VERSION 5.8 ;
BUSBITCHARS "[]" ;
DIVIDERCHAR "/" ;
UNITS
    DATABASE MICRONS 1000 ;
END UNITS

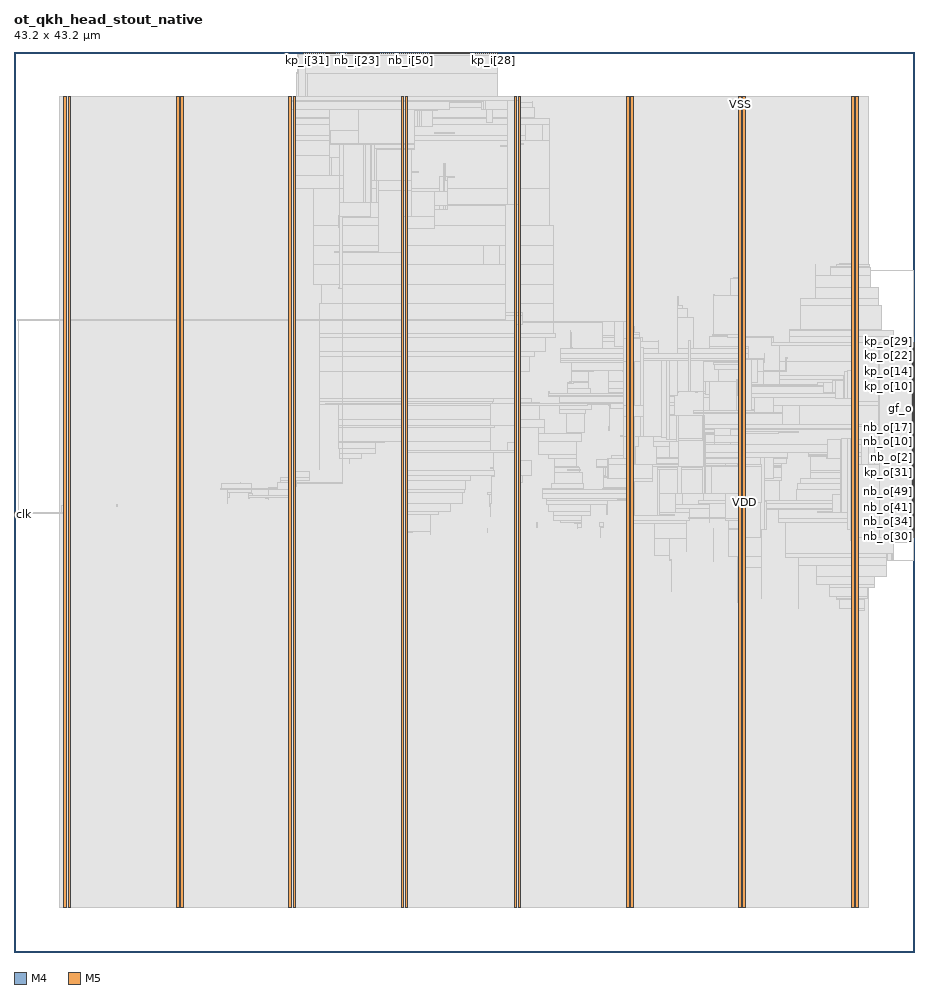
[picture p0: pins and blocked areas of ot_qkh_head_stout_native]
MACRO ot_qkh_head_stout_native
  FOREIGN ot_qkh_head_stout_native 0 0 ;
  CLASS BLOCK ;
  SIZE 43.2 BY 43.2 ;
  PIN clk
    DIRECTION INPUT ;
    USE SIGNAL ;
    PORT
      LAYER M4 ;
        RECT  0 20.976 0.084 21 ;
    END
  END clk
  PIN gf_i
    DIRECTION INPUT ;
    USE SIGNAL ;
    PORT
      LAYER M5 ;
        RECT  20.208 43.116 20.232 43.2 ;
    END
  END gf_i
  PIN gf_o
    DIRECTION OUTPUT ;
    USE SIGNAL ;
    PORT
      LAYER M4 ;
        RECT  43.116 26.064 43.2 26.088 ;
    END
  END gf_o
  PIN kp_i[0]
    DIRECTION INPUT ;
    USE SIGNAL ;
    PORT
      LAYER M5 ;
        RECT  20.304 43.116 20.328 43.2 ;
    END
  END kp_i[0]
  PIN kp_i[10]
    DIRECTION INPUT ;
    USE SIGNAL ;
    PORT
      LAYER M5 ;
        RECT  21.264 43.116 21.288 43.2 ;
    END
  END kp_i[10]
  PIN kp_i[11]
    DIRECTION INPUT ;
    USE SIGNAL ;
    PORT
      LAYER M5 ;
        RECT  21.36 43.116 21.384 43.2 ;
    END
  END kp_i[11]
  PIN kp_i[12]
    DIRECTION INPUT ;
    USE SIGNAL ;
    PORT
      LAYER M5 ;
        RECT  21.456 43.116 21.48 43.2 ;
    END
  END kp_i[12]
  PIN kp_i[13]
    DIRECTION INPUT ;
    USE SIGNAL ;
    PORT
      LAYER M5 ;
        RECT  21.552 43.116 21.576 43.2 ;
    END
  END kp_i[13]
  PIN kp_i[14]
    DIRECTION INPUT ;
    USE SIGNAL ;
    PORT
      LAYER M5 ;
        RECT  21.648 43.116 21.672 43.2 ;
    END
  END kp_i[14]
  PIN kp_i[15]
    DIRECTION INPUT ;
    USE SIGNAL ;
    PORT
      LAYER M5 ;
        RECT  21.744 43.116 21.768 43.2 ;
    END
  END kp_i[15]
  PIN kp_i[16]
    DIRECTION INPUT ;
    USE SIGNAL ;
    PORT
      LAYER M5 ;
        RECT  21.84 43.116 21.864 43.2 ;
    END
  END kp_i[16]
  PIN kp_i[17]
    DIRECTION INPUT ;
    USE SIGNAL ;
    PORT
      LAYER M5 ;
        RECT  21.936 43.116 21.96 43.2 ;
    END
  END kp_i[17]
  PIN kp_i[18]
    DIRECTION INPUT ;
    USE SIGNAL ;
    PORT
      LAYER M5 ;
        RECT  22.032 43.116 22.056 43.2 ;
    END
  END kp_i[18]
  PIN kp_i[19]
    DIRECTION INPUT ;
    USE SIGNAL ;
    PORT
      LAYER M5 ;
        RECT  22.128 43.116 22.152 43.2 ;
    END
  END kp_i[19]
  PIN kp_i[1]
    DIRECTION INPUT ;
    USE SIGNAL ;
    PORT
      LAYER M5 ;
        RECT  20.4 43.116 20.424 43.2 ;
    END
  END kp_i[1]
  PIN kp_i[20]
    DIRECTION INPUT ;
    USE SIGNAL ;
    PORT
      LAYER M5 ;
        RECT  22.224 43.116 22.248 43.2 ;
    END
  END kp_i[20]
  PIN kp_i[21]
    DIRECTION INPUT ;
    USE SIGNAL ;
    PORT
      LAYER M5 ;
        RECT  22.32 43.116 22.344 43.2 ;
    END
  END kp_i[21]
  PIN kp_i[22]
    DIRECTION INPUT ;
    USE SIGNAL ;
    PORT
      LAYER M5 ;
        RECT  22.416 43.116 22.44 43.2 ;
    END
  END kp_i[22]
  PIN kp_i[23]
    DIRECTION INPUT ;
    USE SIGNAL ;
    PORT
      LAYER M5 ;
        RECT  22.512 43.116 22.536 43.2 ;
    END
  END kp_i[23]
  PIN kp_i[24]
    DIRECTION INPUT ;
    USE SIGNAL ;
    PORT
      LAYER M5 ;
        RECT  22.608 43.116 22.632 43.2 ;
    END
  END kp_i[24]
  PIN kp_i[25]
    DIRECTION INPUT ;
    USE SIGNAL ;
    PORT
      LAYER M5 ;
        RECT  22.704 43.116 22.728 43.2 ;
    END
  END kp_i[25]
  PIN kp_i[26]
    DIRECTION INPUT ;
    USE SIGNAL ;
    PORT
      LAYER M5 ;
        RECT  22.8 43.116 22.824 43.2 ;
    END
  END kp_i[26]
  PIN kp_i[27]
    DIRECTION INPUT ;
    USE SIGNAL ;
    PORT
      LAYER M5 ;
        RECT  22.896 43.116 22.92 43.2 ;
    END
  END kp_i[27]
  PIN kp_i[28]
    DIRECTION INPUT ;
    USE SIGNAL ;
    PORT
      LAYER M5 ;
        RECT  22.992 43.116 23.016 43.2 ;
    END
  END kp_i[28]
  PIN kp_i[29]
    DIRECTION INPUT ;
    USE SIGNAL ;
    PORT
      LAYER M5 ;
        RECT  23.088 43.116 23.112 43.2 ;
    END
  END kp_i[29]
  PIN kp_i[2]
    DIRECTION INPUT ;
    USE SIGNAL ;
    PORT
      LAYER M5 ;
        RECT  20.496 43.116 20.52 43.2 ;
    END
  END kp_i[2]
  PIN kp_i[30]
    DIRECTION INPUT ;
    USE SIGNAL ;
    PORT
      LAYER M5 ;
        RECT  23.184 43.116 23.208 43.2 ;
    END
  END kp_i[30]
  PIN kp_i[31]
    DIRECTION INPUT ;
    USE SIGNAL ;
    PORT
      LAYER M5 ;
        RECT  14.064 43.116 14.088 43.2 ;
    END
  END kp_i[31]
  PIN kp_i[3]
    DIRECTION INPUT ;
    USE SIGNAL ;
    PORT
      LAYER M5 ;
        RECT  20.592 43.116 20.616 43.2 ;
    END
  END kp_i[3]
  PIN kp_i[4]
    DIRECTION INPUT ;
    USE SIGNAL ;
    PORT
      LAYER M5 ;
        RECT  20.688 43.116 20.712 43.2 ;
    END
  END kp_i[4]
  PIN kp_i[5]
    DIRECTION INPUT ;
    USE SIGNAL ;
    PORT
      LAYER M5 ;
        RECT  20.784 43.116 20.808 43.2 ;
    END
  END kp_i[5]
  PIN kp_i[6]
    DIRECTION INPUT ;
    USE SIGNAL ;
    PORT
      LAYER M5 ;
        RECT  20.88 43.116 20.904 43.2 ;
    END
  END kp_i[6]
  PIN kp_i[7]
    DIRECTION INPUT ;
    USE SIGNAL ;
    PORT
      LAYER M5 ;
        RECT  20.976 43.116 21 43.2 ;
    END
  END kp_i[7]
  PIN kp_i[8]
    DIRECTION INPUT ;
    USE SIGNAL ;
    PORT
      LAYER M5 ;
        RECT  21.072 43.116 21.096 43.2 ;
    END
  END kp_i[8]
  PIN kp_i[9]
    DIRECTION INPUT ;
    USE SIGNAL ;
    PORT
      LAYER M5 ;
        RECT  21.168 43.116 21.192 43.2 ;
    END
  END kp_i[9]
  PIN kp_o[0]
    DIRECTION OUTPUT ;
    USE SIGNAL ;
    PORT
      LAYER M4 ;
        RECT  43.116 26.16 43.2 26.184 ;
    END
  END kp_o[0]
  PIN kp_o[10]
    DIRECTION OUTPUT ;
    USE SIGNAL ;
    PORT
      LAYER M4 ;
        RECT  43.116 27.12 43.2 27.144 ;
    END
  END kp_o[10]
  PIN kp_o[11]
    DIRECTION OUTPUT ;
    USE SIGNAL ;
    PORT
      LAYER M4 ;
        RECT  43.116 27.216 43.2 27.24 ;
    END
  END kp_o[11]
  PIN kp_o[12]
    DIRECTION OUTPUT ;
    USE SIGNAL ;
    PORT
      LAYER M4 ;
        RECT  43.116 27.312 43.2 27.336 ;
    END
  END kp_o[12]
  PIN kp_o[13]
    DIRECTION OUTPUT ;
    USE SIGNAL ;
    PORT
      LAYER M4 ;
        RECT  43.116 27.408 43.2 27.432 ;
    END
  END kp_o[13]
  PIN kp_o[14]
    DIRECTION OUTPUT ;
    USE SIGNAL ;
    PORT
      LAYER M4 ;
        RECT  43.116 27.504 43.2 27.528 ;
    END
  END kp_o[14]
  PIN kp_o[15]
    DIRECTION OUTPUT ;
    USE SIGNAL ;
    PORT
      LAYER M4 ;
        RECT  43.116 27.6 43.2 27.624 ;
    END
  END kp_o[15]
  PIN kp_o[16]
    DIRECTION OUTPUT ;
    USE SIGNAL ;
    PORT
      LAYER M4 ;
        RECT  43.116 27.696 43.2 27.72 ;
    END
  END kp_o[16]
  PIN kp_o[17]
    DIRECTION OUTPUT ;
    USE SIGNAL ;
    PORT
      LAYER M4 ;
        RECT  43.116 27.792 43.2 27.816 ;
    END
  END kp_o[17]
  PIN kp_o[18]
    DIRECTION OUTPUT ;
    USE SIGNAL ;
    PORT
      LAYER M4 ;
        RECT  43.116 27.888 43.2 27.912 ;
    END
  END kp_o[18]
  PIN kp_o[19]
    DIRECTION OUTPUT ;
    USE SIGNAL ;
    PORT
      LAYER M4 ;
        RECT  43.116 27.984 43.2 28.008 ;
    END
  END kp_o[19]
  PIN kp_o[1]
    DIRECTION OUTPUT ;
    USE SIGNAL ;
    PORT
      LAYER M4 ;
        RECT  43.116 26.256 43.2 26.28 ;
    END
  END kp_o[1]
  PIN kp_o[20]
    DIRECTION OUTPUT ;
    USE SIGNAL ;
    PORT
      LAYER M4 ;
        RECT  43.116 28.08 43.2 28.104 ;
    END
  END kp_o[20]
  PIN kp_o[21]
    DIRECTION OUTPUT ;
    USE SIGNAL ;
    PORT
      LAYER M4 ;
        RECT  43.116 28.176 43.2 28.2 ;
    END
  END kp_o[21]
  PIN kp_o[22]
    DIRECTION OUTPUT ;
    USE SIGNAL ;
    PORT
      LAYER M4 ;
        RECT  43.116 28.272 43.2 28.296 ;
    END
  END kp_o[22]
  PIN kp_o[23]
    DIRECTION OUTPUT ;
    USE SIGNAL ;
    PORT
      LAYER M4 ;
        RECT  43.116 28.368 43.2 28.392 ;
    END
  END kp_o[23]
  PIN kp_o[24]
    DIRECTION OUTPUT ;
    USE SIGNAL ;
    PORT
      LAYER M4 ;
        RECT  43.116 28.464 43.2 28.488 ;
    END
  END kp_o[24]
  PIN kp_o[25]
    DIRECTION OUTPUT ;
    USE SIGNAL ;
    PORT
      LAYER M4 ;
        RECT  43.116 28.56 43.2 28.584 ;
    END
  END kp_o[25]
  PIN kp_o[26]
    DIRECTION OUTPUT ;
    USE SIGNAL ;
    PORT
      LAYER M4 ;
        RECT  43.116 28.656 43.2 28.68 ;
    END
  END kp_o[26]
  PIN kp_o[27]
    DIRECTION OUTPUT ;
    USE SIGNAL ;
    PORT
      LAYER M4 ;
        RECT  43.116 28.752 43.2 28.776 ;
    END
  END kp_o[27]
  PIN kp_o[28]
    DIRECTION OUTPUT ;
    USE SIGNAL ;
    PORT
      LAYER M4 ;
        RECT  43.116 28.848 43.2 28.872 ;
    END
  END kp_o[28]
  PIN kp_o[29]
    DIRECTION OUTPUT ;
    USE SIGNAL ;
    PORT
      LAYER M4 ;
        RECT  43.116 28.944 43.2 28.968 ;
    END
  END kp_o[29]
  PIN kp_o[2]
    DIRECTION OUTPUT ;
    USE SIGNAL ;
    PORT
      LAYER M4 ;
        RECT  43.116 26.352 43.2 26.376 ;
    END
  END kp_o[2]
  PIN kp_o[30]
    DIRECTION OUTPUT ;
    USE SIGNAL ;
    PORT
      LAYER M4 ;
        RECT  43.116 29.04 43.2 29.064 ;
    END
  END kp_o[30]
  PIN kp_o[31]
    DIRECTION OUTPUT ;
    USE SIGNAL ;
    PORT
      LAYER M4 ;
        RECT  43.116 22.992 43.2 23.016 ;
    END
  END kp_o[31]
  PIN kp_o[3]
    DIRECTION OUTPUT ;
    USE SIGNAL ;
    PORT
      LAYER M4 ;
        RECT  43.116 26.448 43.2 26.472 ;
    END
  END kp_o[3]
  PIN kp_o[4]
    DIRECTION OUTPUT ;
    USE SIGNAL ;
    PORT
      LAYER M4 ;
        RECT  43.116 26.544 43.2 26.568 ;
    END
  END kp_o[4]
  PIN kp_o[5]
    DIRECTION OUTPUT ;
    USE SIGNAL ;
    PORT
      LAYER M4 ;
        RECT  43.116 26.64 43.2 26.664 ;
    END
  END kp_o[5]
  PIN kp_o[6]
    DIRECTION OUTPUT ;
    USE SIGNAL ;
    PORT
      LAYER M4 ;
        RECT  43.116 26.736 43.2 26.76 ;
    END
  END kp_o[6]
  PIN kp_o[7]
    DIRECTION OUTPUT ;
    USE SIGNAL ;
    PORT
      LAYER M4 ;
        RECT  43.116 26.832 43.2 26.856 ;
    END
  END kp_o[7]
  PIN kp_o[8]
    DIRECTION OUTPUT ;
    USE SIGNAL ;
    PORT
      LAYER M4 ;
        RECT  43.116 26.928 43.2 26.952 ;
    END
  END kp_o[8]
  PIN kp_o[9]
    DIRECTION OUTPUT ;
    USE SIGNAL ;
    PORT
      LAYER M4 ;
        RECT  43.116 27.024 43.2 27.048 ;
    END
  END kp_o[9]
  PIN kpv_i
    DIRECTION INPUT ;
    USE SIGNAL ;
    PORT
      LAYER M5 ;
        RECT  14.16 43.116 14.184 43.2 ;
    END
  END kpv_i
  PIN kpv_o
    DIRECTION OUTPUT ;
    USE SIGNAL ;
    PORT
      LAYER M4 ;
        RECT  43.116 23.088 43.2 23.112 ;
    END
  END kpv_o
  PIN nb_i[0]
    DIRECTION INPUT ;
    USE SIGNAL ;
    PORT
      LAYER M5 ;
        RECT  14.256 43.116 14.28 43.2 ;
    END
  END nb_i[0]
  PIN nb_i[10]
    DIRECTION INPUT ;
    USE SIGNAL ;
    PORT
      LAYER M5 ;
        RECT  15.216 43.116 15.24 43.2 ;
    END
  END nb_i[10]
  PIN nb_i[11]
    DIRECTION INPUT ;
    USE SIGNAL ;
    PORT
      LAYER M5 ;
        RECT  15.312 43.116 15.336 43.2 ;
    END
  END nb_i[11]
  PIN nb_i[12]
    DIRECTION INPUT ;
    USE SIGNAL ;
    PORT
      LAYER M5 ;
        RECT  15.408 43.116 15.432 43.2 ;
    END
  END nb_i[12]
  PIN nb_i[13]
    DIRECTION INPUT ;
    USE SIGNAL ;
    PORT
      LAYER M5 ;
        RECT  15.504 43.116 15.528 43.2 ;
    END
  END nb_i[13]
  PIN nb_i[14]
    DIRECTION INPUT ;
    USE SIGNAL ;
    PORT
      LAYER M5 ;
        RECT  15.6 43.116 15.624 43.2 ;
    END
  END nb_i[14]
  PIN nb_i[15]
    DIRECTION INPUT ;
    USE SIGNAL ;
    PORT
      LAYER M5 ;
        RECT  15.696 43.116 15.72 43.2 ;
    END
  END nb_i[15]
  PIN nb_i[16]
    DIRECTION INPUT ;
    USE SIGNAL ;
    PORT
      LAYER M5 ;
        RECT  15.792 43.116 15.816 43.2 ;
    END
  END nb_i[16]
  PIN nb_i[17]
    DIRECTION INPUT ;
    USE SIGNAL ;
    PORT
      LAYER M5 ;
        RECT  15.888 43.116 15.912 43.2 ;
    END
  END nb_i[17]
  PIN nb_i[18]
    DIRECTION INPUT ;
    USE SIGNAL ;
    PORT
      LAYER M5 ;
        RECT  15.984 43.116 16.008 43.2 ;
    END
  END nb_i[18]
  PIN nb_i[19]
    DIRECTION INPUT ;
    USE SIGNAL ;
    PORT
      LAYER M5 ;
        RECT  16.08 43.116 16.104 43.2 ;
    END
  END nb_i[19]
  PIN nb_i[1]
    DIRECTION INPUT ;
    USE SIGNAL ;
    PORT
      LAYER M5 ;
        RECT  14.352 43.116 14.376 43.2 ;
    END
  END nb_i[1]
  PIN nb_i[20]
    DIRECTION INPUT ;
    USE SIGNAL ;
    PORT
      LAYER M5 ;
        RECT  16.176 43.116 16.2 43.2 ;
    END
  END nb_i[20]
  PIN nb_i[21]
    DIRECTION INPUT ;
    USE SIGNAL ;
    PORT
      LAYER M5 ;
        RECT  16.272 43.116 16.296 43.2 ;
    END
  END nb_i[21]
  PIN nb_i[22]
    DIRECTION INPUT ;
    USE SIGNAL ;
    PORT
      LAYER M5 ;
        RECT  16.368 43.116 16.392 43.2 ;
    END
  END nb_i[22]
  PIN nb_i[23]
    DIRECTION INPUT ;
    USE SIGNAL ;
    PORT
      LAYER M5 ;
        RECT  16.464 43.116 16.488 43.2 ;
    END
  END nb_i[23]
  PIN nb_i[24]
    DIRECTION INPUT ;
    USE SIGNAL ;
    PORT
      LAYER M5 ;
        RECT  16.56 43.116 16.584 43.2 ;
    END
  END nb_i[24]
  PIN nb_i[25]
    DIRECTION INPUT ;
    USE SIGNAL ;
    PORT
      LAYER M5 ;
        RECT  16.656 43.116 16.68 43.2 ;
    END
  END nb_i[25]
  PIN nb_i[26]
    DIRECTION INPUT ;
    USE SIGNAL ;
    PORT
      LAYER M5 ;
        RECT  16.752 43.116 16.776 43.2 ;
    END
  END nb_i[26]
  PIN nb_i[27]
    DIRECTION INPUT ;
    USE SIGNAL ;
    PORT
      LAYER M5 ;
        RECT  16.848 43.116 16.872 43.2 ;
    END
  END nb_i[27]
  PIN nb_i[28]
    DIRECTION INPUT ;
    USE SIGNAL ;
    PORT
      LAYER M5 ;
        RECT  16.944 43.116 16.968 43.2 ;
    END
  END nb_i[28]
  PIN nb_i[29]
    DIRECTION INPUT ;
    USE SIGNAL ;
    PORT
      LAYER M5 ;
        RECT  17.04 43.116 17.064 43.2 ;
    END
  END nb_i[29]
  PIN nb_i[2]
    DIRECTION INPUT ;
    USE SIGNAL ;
    PORT
      LAYER M5 ;
        RECT  14.448 43.116 14.472 43.2 ;
    END
  END nb_i[2]
  PIN nb_i[30]
    DIRECTION INPUT ;
    USE SIGNAL ;
    PORT
      LAYER M5 ;
        RECT  17.136 43.116 17.16 43.2 ;
    END
  END nb_i[30]
  PIN nb_i[31]
    DIRECTION INPUT ;
    USE SIGNAL ;
    PORT
      LAYER M5 ;
        RECT  17.232 43.116 17.256 43.2 ;
    END
  END nb_i[31]
  PIN nb_i[32]
    DIRECTION INPUT ;
    USE SIGNAL ;
    PORT
      LAYER M5 ;
        RECT  17.328 43.116 17.352 43.2 ;
    END
  END nb_i[32]
  PIN nb_i[33]
    DIRECTION INPUT ;
    USE SIGNAL ;
    PORT
      LAYER M5 ;
        RECT  17.424 43.116 17.448 43.2 ;
    END
  END nb_i[33]
  PIN nb_i[34]
    DIRECTION INPUT ;
    USE SIGNAL ;
    PORT
      LAYER M5 ;
        RECT  17.52 43.116 17.544 43.2 ;
    END
  END nb_i[34]
  PIN nb_i[35]
    DIRECTION INPUT ;
    USE SIGNAL ;
    PORT
      LAYER M5 ;
        RECT  17.616 43.116 17.64 43.2 ;
    END
  END nb_i[35]
  PIN nb_i[36]
    DIRECTION INPUT ;
    USE SIGNAL ;
    PORT
      LAYER M5 ;
        RECT  17.712 43.116 17.736 43.2 ;
    END
  END nb_i[36]
  PIN nb_i[37]
    DIRECTION INPUT ;
    USE SIGNAL ;
    PORT
      LAYER M5 ;
        RECT  17.808 43.116 17.832 43.2 ;
    END
  END nb_i[37]
  PIN nb_i[38]
    DIRECTION INPUT ;
    USE SIGNAL ;
    PORT
      LAYER M5 ;
        RECT  17.904 43.116 17.928 43.2 ;
    END
  END nb_i[38]
  PIN nb_i[39]
    DIRECTION INPUT ;
    USE SIGNAL ;
    PORT
      LAYER M5 ;
        RECT  18 43.116 18.024 43.2 ;
    END
  END nb_i[39]
  PIN nb_i[3]
    DIRECTION INPUT ;
    USE SIGNAL ;
    PORT
      LAYER M5 ;
        RECT  14.544 43.116 14.568 43.2 ;
    END
  END nb_i[3]
  PIN nb_i[40]
    DIRECTION INPUT ;
    USE SIGNAL ;
    PORT
      LAYER M5 ;
        RECT  18.096 43.116 18.12 43.2 ;
    END
  END nb_i[40]
  PIN nb_i[41]
    DIRECTION INPUT ;
    USE SIGNAL ;
    PORT
      LAYER M5 ;
        RECT  18.192 43.116 18.216 43.2 ;
    END
  END nb_i[41]
  PIN nb_i[42]
    DIRECTION INPUT ;
    USE SIGNAL ;
    PORT
      LAYER M5 ;
        RECT  18.288 43.116 18.312 43.2 ;
    END
  END nb_i[42]
  PIN nb_i[43]
    DIRECTION INPUT ;
    USE SIGNAL ;
    PORT
      LAYER M5 ;
        RECT  18.384 43.116 18.408 43.2 ;
    END
  END nb_i[43]
  PIN nb_i[44]
    DIRECTION INPUT ;
    USE SIGNAL ;
    PORT
      LAYER M5 ;
        RECT  18.48 43.116 18.504 43.2 ;
    END
  END nb_i[44]
  PIN nb_i[45]
    DIRECTION INPUT ;
    USE SIGNAL ;
    PORT
      LAYER M5 ;
        RECT  18.576 43.116 18.6 43.2 ;
    END
  END nb_i[45]
  PIN nb_i[46]
    DIRECTION INPUT ;
    USE SIGNAL ;
    PORT
      LAYER M5 ;
        RECT  18.672 43.116 18.696 43.2 ;
    END
  END nb_i[46]
  PIN nb_i[47]
    DIRECTION INPUT ;
    USE SIGNAL ;
    PORT
      LAYER M5 ;
        RECT  18.768 43.116 18.792 43.2 ;
    END
  END nb_i[47]
  PIN nb_i[48]
    DIRECTION INPUT ;
    USE SIGNAL ;
    PORT
      LAYER M5 ;
        RECT  18.864 43.116 18.888 43.2 ;
    END
  END nb_i[48]
  PIN nb_i[49]
    DIRECTION INPUT ;
    USE SIGNAL ;
    PORT
      LAYER M5 ;
        RECT  18.96 43.116 18.984 43.2 ;
    END
  END nb_i[49]
  PIN nb_i[4]
    DIRECTION INPUT ;
    USE SIGNAL ;
    PORT
      LAYER M5 ;
        RECT  14.64 43.116 14.664 43.2 ;
    END
  END nb_i[4]
  PIN nb_i[50]
    DIRECTION INPUT ;
    USE SIGNAL ;
    PORT
      LAYER M5 ;
        RECT  19.056 43.116 19.08 43.2 ;
    END
  END nb_i[50]
  PIN nb_i[51]
    DIRECTION INPUT ;
    USE SIGNAL ;
    PORT
      LAYER M5 ;
        RECT  19.152 43.116 19.176 43.2 ;
    END
  END nb_i[51]
  PIN nb_i[52]
    DIRECTION INPUT ;
    USE SIGNAL ;
    PORT
      LAYER M5 ;
        RECT  19.248 43.116 19.272 43.2 ;
    END
  END nb_i[52]
  PIN nb_i[53]
    DIRECTION INPUT ;
    USE SIGNAL ;
    PORT
      LAYER M5 ;
        RECT  19.344 43.116 19.368 43.2 ;
    END
  END nb_i[53]
  PIN nb_i[54]
    DIRECTION INPUT ;
    USE SIGNAL ;
    PORT
      LAYER M5 ;
        RECT  19.44 43.116 19.464 43.2 ;
    END
  END nb_i[54]
  PIN nb_i[55]
    DIRECTION INPUT ;
    USE SIGNAL ;
    PORT
      LAYER M5 ;
        RECT  19.536 43.116 19.56 43.2 ;
    END
  END nb_i[55]
  PIN nb_i[56]
    DIRECTION INPUT ;
    USE SIGNAL ;
    PORT
      LAYER M5 ;
        RECT  19.632 43.116 19.656 43.2 ;
    END
  END nb_i[56]
  PIN nb_i[57]
    DIRECTION INPUT ;
    USE SIGNAL ;
    PORT
      LAYER M5 ;
        RECT  19.728 43.116 19.752 43.2 ;
    END
  END nb_i[57]
  PIN nb_i[58]
    DIRECTION INPUT ;
    USE SIGNAL ;
    PORT
      LAYER M5 ;
        RECT  19.824 43.116 19.848 43.2 ;
    END
  END nb_i[58]
  PIN nb_i[59]
    DIRECTION INPUT ;
    USE SIGNAL ;
    PORT
      LAYER M5 ;
        RECT  19.92 43.116 19.944 43.2 ;
    END
  END nb_i[59]
  PIN nb_i[5]
    DIRECTION INPUT ;
    USE SIGNAL ;
    PORT
      LAYER M5 ;
        RECT  14.736 43.116 14.76 43.2 ;
    END
  END nb_i[5]
  PIN nb_i[60]
    DIRECTION INPUT ;
    USE SIGNAL ;
    PORT
      LAYER M5 ;
        RECT  20.016 43.116 20.04 43.2 ;
    END
  END nb_i[60]
  PIN nb_i[61]
    DIRECTION INPUT ;
    USE SIGNAL ;
    PORT
      LAYER M5 ;
        RECT  20.112 43.116 20.136 43.2 ;
    END
  END nb_i[61]
  PIN nb_i[62]
    DIRECTION INPUT ;
    USE SIGNAL ;
    PORT
      LAYER M5 ;
        RECT  13.872 43.116 13.896 43.2 ;
    END
  END nb_i[62]
  PIN nb_i[63]
    DIRECTION INPUT ;
    USE SIGNAL ;
    PORT
      LAYER M5 ;
        RECT  13.968 43.116 13.992 43.2 ;
    END
  END nb_i[63]
  PIN nb_i[6]
    DIRECTION INPUT ;
    USE SIGNAL ;
    PORT
      LAYER M5 ;
        RECT  14.832 43.116 14.856 43.2 ;
    END
  END nb_i[6]
  PIN nb_i[7]
    DIRECTION INPUT ;
    USE SIGNAL ;
    PORT
      LAYER M5 ;
        RECT  14.928 43.116 14.952 43.2 ;
    END
  END nb_i[7]
  PIN nb_i[8]
    DIRECTION INPUT ;
    USE SIGNAL ;
    PORT
      LAYER M5 ;
        RECT  15.024 43.116 15.048 43.2 ;
    END
  END nb_i[8]
  PIN nb_i[9]
    DIRECTION INPUT ;
    USE SIGNAL ;
    PORT
      LAYER M5 ;
        RECT  15.12 43.116 15.144 43.2 ;
    END
  END nb_i[9]
  PIN nb_o[0]
    DIRECTION OUTPUT ;
    USE SIGNAL ;
    PORT
      LAYER M4 ;
        RECT  43.116 23.184 43.2 23.208 ;
    END
  END nb_o[0]
  PIN nb_o[10]
    DIRECTION OUTPUT ;
    USE SIGNAL ;
    PORT
      LAYER M4 ;
        RECT  43.116 24.144 43.2 24.168 ;
    END
  END nb_o[10]
  PIN nb_o[11]
    DIRECTION OUTPUT ;
    USE SIGNAL ;
    PORT
      LAYER M4 ;
        RECT  43.116 24.24 43.2 24.264 ;
    END
  END nb_o[11]
  PIN nb_o[12]
    DIRECTION OUTPUT ;
    USE SIGNAL ;
    PORT
      LAYER M4 ;
        RECT  43.116 24.336 43.2 24.36 ;
    END
  END nb_o[12]
  PIN nb_o[13]
    DIRECTION OUTPUT ;
    USE SIGNAL ;
    PORT
      LAYER M4 ;
        RECT  43.116 24.432 43.2 24.456 ;
    END
  END nb_o[13]
  PIN nb_o[14]
    DIRECTION OUTPUT ;
    USE SIGNAL ;
    PORT
      LAYER M4 ;
        RECT  43.116 24.528 43.2 24.552 ;
    END
  END nb_o[14]
  PIN nb_o[15]
    DIRECTION OUTPUT ;
    USE SIGNAL ;
    PORT
      LAYER M4 ;
        RECT  43.116 24.624 43.2 24.648 ;
    END
  END nb_o[15]
  PIN nb_o[16]
    DIRECTION OUTPUT ;
    USE SIGNAL ;
    PORT
      LAYER M4 ;
        RECT  43.116 24.72 43.2 24.744 ;
    END
  END nb_o[16]
  PIN nb_o[17]
    DIRECTION OUTPUT ;
    USE SIGNAL ;
    PORT
      LAYER M4 ;
        RECT  43.116 24.816 43.2 24.84 ;
    END
  END nb_o[17]
  PIN nb_o[18]
    DIRECTION OUTPUT ;
    USE SIGNAL ;
    PORT
      LAYER M4 ;
        RECT  43.116 24.912 43.2 24.936 ;
    END
  END nb_o[18]
  PIN nb_o[19]
    DIRECTION OUTPUT ;
    USE SIGNAL ;
    PORT
      LAYER M4 ;
        RECT  43.116 25.008 43.2 25.032 ;
    END
  END nb_o[19]
  PIN nb_o[1]
    DIRECTION OUTPUT ;
    USE SIGNAL ;
    PORT
      LAYER M4 ;
        RECT  43.116 23.28 43.2 23.304 ;
    END
  END nb_o[1]
  PIN nb_o[20]
    DIRECTION OUTPUT ;
    USE SIGNAL ;
    PORT
      LAYER M4 ;
        RECT  43.116 25.104 43.2 25.128 ;
    END
  END nb_o[20]
  PIN nb_o[21]
    DIRECTION OUTPUT ;
    USE SIGNAL ;
    PORT
      LAYER M4 ;
        RECT  43.116 25.2 43.2 25.224 ;
    END
  END nb_o[21]
  PIN nb_o[22]
    DIRECTION OUTPUT ;
    USE SIGNAL ;
    PORT
      LAYER M4 ;
        RECT  43.116 25.296 43.2 25.32 ;
    END
  END nb_o[22]
  PIN nb_o[23]
    DIRECTION OUTPUT ;
    USE SIGNAL ;
    PORT
      LAYER M4 ;
        RECT  43.116 25.392 43.2 25.416 ;
    END
  END nb_o[23]
  PIN nb_o[24]
    DIRECTION OUTPUT ;
    USE SIGNAL ;
    PORT
      LAYER M4 ;
        RECT  43.116 25.488 43.2 25.512 ;
    END
  END nb_o[24]
  PIN nb_o[25]
    DIRECTION OUTPUT ;
    USE SIGNAL ;
    PORT
      LAYER M4 ;
        RECT  43.116 25.584 43.2 25.608 ;
    END
  END nb_o[25]
  PIN nb_o[26]
    DIRECTION OUTPUT ;
    USE SIGNAL ;
    PORT
      LAYER M4 ;
        RECT  43.116 25.68 43.2 25.704 ;
    END
  END nb_o[26]
  PIN nb_o[27]
    DIRECTION OUTPUT ;
    USE SIGNAL ;
    PORT
      LAYER M4 ;
        RECT  43.116 25.776 43.2 25.8 ;
    END
  END nb_o[27]
  PIN nb_o[28]
    DIRECTION OUTPUT ;
    USE SIGNAL ;
    PORT
      LAYER M4 ;
        RECT  43.116 25.872 43.2 25.896 ;
    END
  END nb_o[28]
  PIN nb_o[29]
    DIRECTION OUTPUT ;
    USE SIGNAL ;
    PORT
      LAYER M4 ;
        RECT  43.116 25.968 43.2 25.992 ;
    END
  END nb_o[29]
  PIN nb_o[2]
    DIRECTION OUTPUT ;
    USE SIGNAL ;
    PORT
      LAYER M4 ;
        RECT  43.116 23.376 43.2 23.4 ;
    END
  END nb_o[2]
  PIN nb_o[30]
    DIRECTION OUTPUT ;
    USE SIGNAL ;
    PORT
      LAYER M4 ;
        RECT  43.116 19.92 43.2 19.944 ;
    END
  END nb_o[30]
  PIN nb_o[31]
    DIRECTION OUTPUT ;
    USE SIGNAL ;
    PORT
      LAYER M4 ;
        RECT  43.116 20.016 43.2 20.04 ;
    END
  END nb_o[31]
  PIN nb_o[32]
    DIRECTION OUTPUT ;
    USE SIGNAL ;
    PORT
      LAYER M4 ;
        RECT  43.116 20.112 43.2 20.136 ;
    END
  END nb_o[32]
  PIN nb_o[33]
    DIRECTION OUTPUT ;
    USE SIGNAL ;
    PORT
      LAYER M4 ;
        RECT  43.116 20.208 43.2 20.232 ;
    END
  END nb_o[33]
  PIN nb_o[34]
    DIRECTION OUTPUT ;
    USE SIGNAL ;
    PORT
      LAYER M4 ;
        RECT  43.116 20.304 43.2 20.328 ;
    END
  END nb_o[34]
  PIN nb_o[35]
    DIRECTION OUTPUT ;
    USE SIGNAL ;
    PORT
      LAYER M4 ;
        RECT  43.116 20.4 43.2 20.424 ;
    END
  END nb_o[35]
  PIN nb_o[36]
    DIRECTION OUTPUT ;
    USE SIGNAL ;
    PORT
      LAYER M4 ;
        RECT  43.116 20.496 43.2 20.52 ;
    END
  END nb_o[36]
  PIN nb_o[37]
    DIRECTION OUTPUT ;
    USE SIGNAL ;
    PORT
      LAYER M4 ;
        RECT  43.116 20.592 43.2 20.616 ;
    END
  END nb_o[37]
  PIN nb_o[38]
    DIRECTION OUTPUT ;
    USE SIGNAL ;
    PORT
      LAYER M4 ;
        RECT  43.116 20.688 43.2 20.712 ;
    END
  END nb_o[38]
  PIN nb_o[39]
    DIRECTION OUTPUT ;
    USE SIGNAL ;
    PORT
      LAYER M4 ;
        RECT  43.116 20.784 43.2 20.808 ;
    END
  END nb_o[39]
  PIN nb_o[3]
    DIRECTION OUTPUT ;
    USE SIGNAL ;
    PORT
      LAYER M4 ;
        RECT  43.116 23.472 43.2 23.496 ;
    END
  END nb_o[3]
  PIN nb_o[40]
    DIRECTION OUTPUT ;
    USE SIGNAL ;
    PORT
      LAYER M4 ;
        RECT  43.116 20.88 43.2 20.904 ;
    END
  END nb_o[40]
  PIN nb_o[41]
    DIRECTION OUTPUT ;
    USE SIGNAL ;
    PORT
      LAYER M4 ;
        RECT  43.116 20.976 43.2 21 ;
    END
  END nb_o[41]
  PIN nb_o[42]
    DIRECTION OUTPUT ;
    USE SIGNAL ;
    PORT
      LAYER M4 ;
        RECT  43.116 21.072 43.2 21.096 ;
    END
  END nb_o[42]
  PIN nb_o[43]
    DIRECTION OUTPUT ;
    USE SIGNAL ;
    PORT
      LAYER M4 ;
        RECT  43.116 21.168 43.2 21.192 ;
    END
  END nb_o[43]
  PIN nb_o[44]
    DIRECTION OUTPUT ;
    USE SIGNAL ;
    PORT
      LAYER M4 ;
        RECT  43.116 21.264 43.2 21.288 ;
    END
  END nb_o[44]
  PIN nb_o[45]
    DIRECTION OUTPUT ;
    USE SIGNAL ;
    PORT
      LAYER M4 ;
        RECT  43.116 21.36 43.2 21.384 ;
    END
  END nb_o[45]
  PIN nb_o[46]
    DIRECTION OUTPUT ;
    USE SIGNAL ;
    PORT
      LAYER M4 ;
        RECT  43.116 21.456 43.2 21.48 ;
    END
  END nb_o[46]
  PIN nb_o[47]
    DIRECTION OUTPUT ;
    USE SIGNAL ;
    PORT
      LAYER M4 ;
        RECT  43.116 21.552 43.2 21.576 ;
    END
  END nb_o[47]
  PIN nb_o[48]
    DIRECTION OUTPUT ;
    USE SIGNAL ;
    PORT
      LAYER M4 ;
        RECT  43.116 21.648 43.2 21.672 ;
    END
  END nb_o[48]
  PIN nb_o[49]
    DIRECTION OUTPUT ;
    USE SIGNAL ;
    PORT
      LAYER M4 ;
        RECT  43.116 21.744 43.2 21.768 ;
    END
  END nb_o[49]
  PIN nb_o[4]
    DIRECTION OUTPUT ;
    USE SIGNAL ;
    PORT
      LAYER M4 ;
        RECT  43.116 23.568 43.2 23.592 ;
    END
  END nb_o[4]
  PIN nb_o[50]
    DIRECTION OUTPUT ;
    USE SIGNAL ;
    PORT
      LAYER M4 ;
        RECT  43.116 21.84 43.2 21.864 ;
    END
  END nb_o[50]
  PIN nb_o[51]
    DIRECTION OUTPUT ;
    USE SIGNAL ;
    PORT
      LAYER M4 ;
        RECT  43.116 21.936 43.2 21.96 ;
    END
  END nb_o[51]
  PIN nb_o[52]
    DIRECTION OUTPUT ;
    USE SIGNAL ;
    PORT
      LAYER M4 ;
        RECT  43.116 22.032 43.2 22.056 ;
    END
  END nb_o[52]
  PIN nb_o[53]
    DIRECTION OUTPUT ;
    USE SIGNAL ;
    PORT
      LAYER M4 ;
        RECT  43.116 22.128 43.2 22.152 ;
    END
  END nb_o[53]
  PIN nb_o[54]
    DIRECTION OUTPUT ;
    USE SIGNAL ;
    PORT
      LAYER M4 ;
        RECT  43.116 22.224 43.2 22.248 ;
    END
  END nb_o[54]
  PIN nb_o[55]
    DIRECTION OUTPUT ;
    USE SIGNAL ;
    PORT
      LAYER M4 ;
        RECT  43.116 22.32 43.2 22.344 ;
    END
  END nb_o[55]
  PIN nb_o[56]
    DIRECTION OUTPUT ;
    USE SIGNAL ;
    PORT
      LAYER M4 ;
        RECT  43.116 22.416 43.2 22.44 ;
    END
  END nb_o[56]
  PIN nb_o[57]
    DIRECTION OUTPUT ;
    USE SIGNAL ;
    PORT
      LAYER M4 ;
        RECT  43.116 22.512 43.2 22.536 ;
    END
  END nb_o[57]
  PIN nb_o[58]
    DIRECTION OUTPUT ;
    USE SIGNAL ;
    PORT
      LAYER M4 ;
        RECT  43.116 22.608 43.2 22.632 ;
    END
  END nb_o[58]
  PIN nb_o[59]
    DIRECTION OUTPUT ;
    USE SIGNAL ;
    PORT
      LAYER M4 ;
        RECT  43.116 22.704 43.2 22.728 ;
    END
  END nb_o[59]
  PIN nb_o[5]
    DIRECTION OUTPUT ;
    USE SIGNAL ;
    PORT
      LAYER M4 ;
        RECT  43.116 23.664 43.2 23.688 ;
    END
  END nb_o[5]
  PIN nb_o[60]
    DIRECTION OUTPUT ;
    USE SIGNAL ;
    PORT
      LAYER M4 ;
        RECT  43.116 22.8 43.2 22.824 ;
    END
  END nb_o[60]
  PIN nb_o[61]
    DIRECTION OUTPUT ;
    USE SIGNAL ;
    PORT
      LAYER M4 ;
        RECT  43.116 22.896 43.2 22.92 ;
    END
  END nb_o[61]
  PIN nb_o[62]
    DIRECTION OUTPUT ;
    USE SIGNAL ;
    PORT
      LAYER M4 ;
        RECT  43.116 29.136 43.2 29.16 ;
    END
  END nb_o[62]
  PIN nb_o[63]
    DIRECTION OUTPUT ;
    USE SIGNAL ;
    PORT
      LAYER M4 ;
        RECT  43.116 29.232 43.2 29.256 ;
    END
  END nb_o[63]
  PIN nb_o[6]
    DIRECTION OUTPUT ;
    USE SIGNAL ;
    PORT
      LAYER M4 ;
        RECT  43.116 23.76 43.2 23.784 ;
    END
  END nb_o[6]
  PIN nb_o[7]
    DIRECTION OUTPUT ;
    USE SIGNAL ;
    PORT
      LAYER M4 ;
        RECT  43.116 23.856 43.2 23.88 ;
    END
  END nb_o[7]
  PIN nb_o[8]
    DIRECTION OUTPUT ;
    USE SIGNAL ;
    PORT
      LAYER M4 ;
        RECT  43.116 23.952 43.2 23.976 ;
    END
  END nb_o[8]
  PIN nb_o[9]
    DIRECTION OUTPUT ;
    USE SIGNAL ;
    PORT
      LAYER M4 ;
        RECT  43.116 24.048 43.2 24.072 ;
    END
  END nb_o[9]
  PIN rst_n
    DIRECTION INPUT ;
    USE SIGNAL ;
    PORT
      LAYER M4 ;
        RECT  0 21.072 0.084 21.096 ;
    END
  END rst_n
  PIN VDD
    DIRECTION INOUT ;
    USE POWER ;
    PORT
      LAYER M5 ;
        RECT  40.392 2.151 40.512 41.049 ;
        RECT  34.992 2.151 35.112 41.049 ;
        RECT  29.592 2.151 29.712 41.049 ;
        RECT  24.192 2.151 24.312 41.049 ;
        RECT  18.792 2.151 18.912 41.049 ;
        RECT  13.392 2.151 13.512 41.049 ;
        RECT  7.992 2.151 8.112 41.049 ;
        RECT  2.592 2.151 2.712 41.049 ;
    END
  END VDD
  PIN VSS
    DIRECTION INOUT ;
    USE GROUND ;
    PORT
      LAYER M5 ;
        RECT  40.2 2.137 40.32 41.063 ;
        RECT  34.8 2.137 34.92 41.063 ;
        RECT  29.4 2.137 29.52 41.063 ;
        RECT  24 2.137 24.12 41.063 ;
        RECT  18.6 2.137 18.72 41.063 ;
        RECT  13.2 2.137 13.32 41.063 ;
        RECT  7.8 2.137 7.92 41.063 ;
        RECT  2.4 2.137 2.52 41.063 ;
    END
  END VSS
  # OT_OBS_CLOSED layer=M5 d_um=1.536 added=17
  OBS
    LAYER RVTN ;
     RECT  2.16 2.16 41.04 2.295 ;
     RECT  2.16 2.565 41.04 2.835 ;
     RECT  2.16 3.105 41.04 3.375 ;
     RECT  2.16 3.645 41.04 3.915 ;
     RECT  2.16 4.185 41.04 4.455 ;
     RECT  2.16 4.725 41.04 4.995 ;
     RECT  2.16 5.265 41.04 5.535 ;
     RECT  2.16 5.805 41.04 6.075 ;
     RECT  2.16 6.345 41.04 6.615 ;
     RECT  2.16 6.885 41.04 7.155 ;
     RECT  2.16 7.425 41.04 7.695 ;
     RECT  2.16 7.965 41.04 8.235 ;
     RECT  2.16 8.505 41.04 8.775 ;
     RECT  2.16 9.045 41.04 9.315 ;
     RECT  2.16 9.585 41.04 9.855 ;
     RECT  2.16 10.125 41.04 10.395 ;
     RECT  2.16 10.665 41.04 10.935 ;
     RECT  2.16 11.205 41.04 11.475 ;
     RECT  2.16 11.745 41.04 12.015 ;
     RECT  2.16 12.285 41.04 12.555 ;
     RECT  2.16 12.825 41.04 13.095 ;
     RECT  2.16 13.365 41.04 13.635 ;
     RECT  2.16 13.905 41.04 14.175 ;
     RECT  2.16 14.445 41.04 14.715 ;
     RECT  2.16 14.985 41.04 15.255 ;
     RECT  2.16 15.525 41.04 15.795 ;
     RECT  2.16 16.065 41.04 16.335 ;
     RECT  2.16 16.605 41.04 16.875 ;
     RECT  2.16 17.145 41.04 17.415 ;
     RECT  2.16 17.685 41.04 17.955 ;
     RECT  2.16 18.225 41.04 18.495 ;
     RECT  2.16 18.765 41.04 19.035 ;
     RECT  2.16 19.305 41.04 19.575 ;
     RECT  2.16 19.845 41.04 20.115 ;
     RECT  2.16 20.385 41.04 20.655 ;
     RECT  2.16 20.925 41.04 21.195 ;
     RECT  2.16 21.465 41.04 21.735 ;
     RECT  2.16 22.005 41.04 22.275 ;
     RECT  2.16 22.545 41.04 22.815 ;
     RECT  2.16 23.085 41.04 23.355 ;
     RECT  2.16 23.625 41.04 23.895 ;
     RECT  2.16 24.165 41.04 24.435 ;
     RECT  2.16 24.705 41.04 24.975 ;
     RECT  2.16 25.245 41.04 25.515 ;
     RECT  2.16 25.785 41.04 26.055 ;
     RECT  2.16 26.325 41.04 26.595 ;
     RECT  2.16 26.865 41.04 27.135 ;
     RECT  2.16 27.405 41.04 27.675 ;
     RECT  2.16 27.945 41.04 28.215 ;
     RECT  2.16 28.485 41.04 28.755 ;
     RECT  2.16 29.025 41.04 29.295 ;
     RECT  2.16 29.565 41.04 29.835 ;
     RECT  2.16 30.105 41.04 30.375 ;
     RECT  2.16 30.645 41.04 30.915 ;
     RECT  2.16 31.185 41.04 31.455 ;
     RECT  2.16 31.725 41.04 31.995 ;
     RECT  2.16 32.265 41.04 32.535 ;
     RECT  2.16 32.805 41.04 33.075 ;
     RECT  2.16 33.345 41.04 33.615 ;
     RECT  2.16 33.885 41.04 34.155 ;
     RECT  2.16 34.425 41.04 34.695 ;
     RECT  2.16 34.965 41.04 35.235 ;
     RECT  2.16 35.505 41.04 35.775 ;
     RECT  2.16 36.045 41.04 36.315 ;
     RECT  2.16 36.585 41.04 36.855 ;
     RECT  2.16 37.125 41.04 37.395 ;
     RECT  2.16 37.665 41.04 37.935 ;
     RECT  2.16 38.205 41.04 38.475 ;
     RECT  2.16 38.745 41.04 39.015 ;
     RECT  2.16 39.285 41.04 39.555 ;
     RECT  2.16 39.825 41.04 40.095 ;
     RECT  2.16 40.365 41.04 40.635 ;
     RECT  2.16 40.905 41.04 41.04 ;
    LAYER RVTP ;
     RECT  2.16 2.295 41.04 2.565 ;
     RECT  2.16 2.835 41.04 3.105 ;
     RECT  2.16 3.375 41.04 3.645 ;
     RECT  2.16 3.915 41.04 4.185 ;
     RECT  2.16 4.455 41.04 4.725 ;
     RECT  2.16 4.995 41.04 5.265 ;
     RECT  2.16 5.535 41.04 5.805 ;
     RECT  2.16 6.075 41.04 6.345 ;
     RECT  2.16 6.615 41.04 6.885 ;
     RECT  2.16 7.155 41.04 7.425 ;
     RECT  2.16 7.695 41.04 7.965 ;
     RECT  2.16 8.235 41.04 8.505 ;
     RECT  2.16 8.775 41.04 9.045 ;
     RECT  2.16 9.315 41.04 9.585 ;
     RECT  2.16 9.855 41.04 10.125 ;
     RECT  2.16 10.395 41.04 10.665 ;
     RECT  2.16 10.935 41.04 11.205 ;
     RECT  2.16 11.475 41.04 11.745 ;
     RECT  2.16 12.015 41.04 12.285 ;
     RECT  2.16 12.555 41.04 12.825 ;
     RECT  2.16 13.095 41.04 13.365 ;
     RECT  2.16 13.635 41.04 13.905 ;
     RECT  2.16 14.175 41.04 14.445 ;
     RECT  2.16 14.715 41.04 14.985 ;
     RECT  2.16 15.255 41.04 15.525 ;
     RECT  2.16 15.795 41.04 16.065 ;
     RECT  2.16 16.335 41.04 16.605 ;
     RECT  2.16 16.875 41.04 17.145 ;
     RECT  2.16 17.415 41.04 17.685 ;
     RECT  2.16 17.955 41.04 18.225 ;
     RECT  2.16 18.495 41.04 18.765 ;
     RECT  2.16 19.035 41.04 19.305 ;
     RECT  2.16 19.575 41.04 19.845 ;
     RECT  2.16 20.115 41.04 20.385 ;
     RECT  2.16 20.655 41.04 20.925 ;
     RECT  2.16 21.195 41.04 21.465 ;
     RECT  2.16 21.735 41.04 22.005 ;
     RECT  2.16 22.275 41.04 22.545 ;
     RECT  2.16 22.815 41.04 23.085 ;
     RECT  2.16 23.355 41.04 23.625 ;
     RECT  2.16 23.895 41.04 24.165 ;
     RECT  2.16 24.435 41.04 24.705 ;
     RECT  2.16 24.975 41.04 25.245 ;
     RECT  2.16 25.515 41.04 25.785 ;
     RECT  2.16 26.055 41.04 26.325 ;
     RECT  2.16 26.595 41.04 26.865 ;
     RECT  2.16 27.135 41.04 27.405 ;
     RECT  2.16 27.675 41.04 27.945 ;
     RECT  2.16 28.215 41.04 28.485 ;
     RECT  2.16 28.755 41.04 29.025 ;
     RECT  2.16 29.295 41.04 29.565 ;
     RECT  2.16 29.835 41.04 30.105 ;
     RECT  2.16 30.375 41.04 30.645 ;
     RECT  2.16 30.915 41.04 31.185 ;
     RECT  2.16 31.455 41.04 31.725 ;
     RECT  2.16 31.995 41.04 32.265 ;
     RECT  2.16 32.535 41.04 32.805 ;
     RECT  2.16 33.075 41.04 33.345 ;
     RECT  2.16 33.615 41.04 33.885 ;
     RECT  2.16 34.155 41.04 34.425 ;
     RECT  2.16 34.695 41.04 34.965 ;
     RECT  2.16 35.235 41.04 35.505 ;
     RECT  2.16 35.775 41.04 36.045 ;
     RECT  2.16 36.315 41.04 36.585 ;
     RECT  2.16 36.855 41.04 37.125 ;
     RECT  2.16 37.395 41.04 37.665 ;
     RECT  2.16 37.935 41.04 38.205 ;
     RECT  2.16 38.475 41.04 38.745 ;
     RECT  2.16 39.015 41.04 39.285 ;
     RECT  2.16 39.555 41.04 39.825 ;
     RECT  2.16 40.095 41.04 40.365 ;
     RECT  2.16 40.635 41.04 40.905 ;
    LAYER M1 ;
     RECT  2.16 2.151 41.04 41.049 ;
    LAYER M2 ;
     RECT  2.16 2.151 41.04 41.049 ;
     RECT  41.04 32.706 41.063 32.994 ;
     RECT  41.063 32.706 41.099 32.832 ;
     RECT  41.04 17.496 41.315 31.014 ;
     RECT  41.04 31.896 41.495 31.914 ;
     RECT  41.315 18.036 41.603 31.014 ;
     RECT  41.603 30.996 41.639 31.014 ;
     RECT  41.603 18.036 41.891 29.826 ;
     RECT  41.891 18.774 41.927 29.826 ;
     RECT  41.927 18.774 42.143 28.476 ;
     RECT  42.143 18.774 42.179 19.944 ;
     RECT  42.143 20.736 42.179 28.476 ;
     RECT  42.179 18.774 42.215 19.674 ;
     RECT  42.179 20.736 42.215 24.462 ;
     RECT  41.927 29.304 42.215 29.826 ;
     RECT  42.215 20.736 42.251 23.724 ;
     RECT  42.215 29.304 42.251 29.556 ;
     RECT  42.251 29.538 42.287 29.556 ;
     RECT  42.179 26.604 43.007 27.702 ;
     RECT  43.007 26.946 43.043 27.702 ;
     RECT  42.251 20.736 43.079 22.806 ;
     RECT  43.043 26.946 43.079 27.36 ;
     RECT  42.215 19.656 43.087 19.674 ;
     RECT  43.087 19.656 43.115 20.304 ;
     RECT  43.079 21.546 43.115 22.806 ;
     RECT  42.251 23.706 43.115 23.724 ;
     RECT  43.079 27.216 43.115 27.36 ;
     RECT  42.215 18.774 43.187 18.792 ;
     RECT  43.115 20.286 43.187 20.304 ;
     RECT  41.099 32.706 43.187 32.724 ;
    LAYER M3 ;
     RECT  2.415 2.143 2.505 2.413 ;
     RECT  7.815 2.143 7.905 2.413 ;
     RECT  13.215 2.143 13.305 2.413 ;
     RECT  18.615 2.143 18.705 2.413 ;
     RECT  24.015 2.143 24.105 2.413 ;
     RECT  29.415 2.143 29.505 2.413 ;
     RECT  34.815 2.143 34.905 2.413 ;
     RECT  40.215 2.143 40.305 2.413 ;
     RECT  40.215 2.413 40.497 16.375 ;
     RECT  40.215 16.375 40.59 16.411 ;
     RECT  40.215 16.411 40.806 16.501 ;
     RECT  34.815 2.413 35.097 16.771 ;
     RECT  39.6 16.501 40.806 16.915 ;
     RECT  39.456 16.915 40.806 16.951 ;
     RECT  39.456 16.951 40.95 17.077 ;
     RECT  39.168 17.077 40.95 17.491 ;
     RECT  39.168 17.491 41.31 17.653 ;
     RECT  38.52 17.653 41.31 18.031 ;
     RECT  34.704 16.771 35.097 18.463 ;
     RECT  35.856 16.951 35.874 18.463 ;
     RECT  37.656 16.501 37.674 18.571 ;
     RECT  38.52 18.031 41.886 18.571 ;
     RECT  31.536 17.311 31.554 18.805 ;
     RECT  31.464 18.805 31.554 18.833 ;
     RECT  37.656 18.571 41.886 18.931 ;
     RECT  34.704 18.463 35.874 18.967 ;
     RECT  31.464 18.833 31.482 19.039 ;
     RECT  37.044 18.931 41.886 19.111 ;
     RECT  43.164 18.769 43.182 19.651 ;
     RECT  30.744 19.039 31.482 19.849 ;
     RECT  32.256 19.201 32.274 19.849 ;
     RECT  18.615 2.413 18.897 20.119 ;
     RECT  18.615 20.119 19.134 20.191 ;
     RECT  19.98 20.047 19.998 20.191 ;
     RECT  34.308 18.967 35.874 20.299 ;
     RECT  33.552 18.733 33.57 20.309 ;
     RECT  43.092 19.651 43.182 20.309 ;
     RECT  43.092 20.309 43.11 20.333 ;
     RECT  22.716 20.119 22.734 20.345 ;
     RECT  34.308 20.299 36.126 20.345 ;
     RECT  28.152 19.885 28.17 20.353 ;
     RECT  27.036 20.317 27.054 20.389 ;
     RECT  28.152 20.353 28.314 20.425 ;
     RECT  27.036 20.389 27.234 20.551 ;
     RECT  29.415 2.413 29.697 20.551 ;
     RECT  30.744 19.849 32.274 20.551 ;
     RECT  25.092 20.353 25.11 20.615 ;
     RECT  28.116 20.425 28.314 20.615 ;
     RECT  37.044 19.111 42.21 20.621 ;
     RECT  26.892 20.551 27.234 20.623 ;
     RECT  37.044 20.621 41.31 20.623 ;
     RECT  42.12 20.621 42.21 20.717 ;
     RECT  26.244 20.623 27.234 20.731 ;
     RECT  29.415 20.551 32.274 20.731 ;
     RECT  34.308 20.345 35.73 20.731 ;
     RECT  36.72 20.623 41.31 20.813 ;
     RECT  25.884 20.731 27.234 20.929 ;
     RECT  18.615 20.191 19.998 21.001 ;
     RECT  2.415 2.413 2.697 21.067 ;
     RECT  29.415 20.731 32.418 21.119 ;
     RECT  18.615 21.001 20.394 21.127 ;
     RECT  25.884 20.929 27.666 21.127 ;
     RECT  34.164 20.731 35.73 21.235 ;
     RECT  34.164 21.235 35.946 21.259 ;
     RECT  36.72 20.813 41.094 21.259 ;
     RECT  31.752 21.119 32.418 21.271 ;
     RECT  33.372 20.623 33.39 21.271 ;
     RECT  34.164 21.259 41.094 21.299 ;
     RECT  22.86 20.893 22.878 21.397 ;
     RECT  2.304 21.067 2.697 21.425 ;
     RECT  4.932 21.361 4.95 21.461 ;
     RECT  25.632 21.127 27.666 21.469 ;
     RECT  28.44 21.001 28.494 21.469 ;
     RECT  42.12 20.717 42.138 21.469 ;
     RECT  31.752 21.271 33.39 21.497 ;
     RECT  18.615 21.127 20.934 21.541 ;
     RECT  22.824 21.397 22.878 21.541 ;
     RECT  32.832 21.497 33.39 21.541 ;
     RECT  34.164 21.299 40.842 21.541 ;
     RECT  42.984 20.731 43.074 21.541 ;
     RECT  32.832 21.541 40.842 21.659 ;
     RECT  25.56 21.469 28.494 21.691 ;
     RECT  29.415 21.119 30.978 21.691 ;
     RECT  42.984 21.541 43.11 21.773 ;
     RECT  12.204 21.739 12.222 21.775 ;
     RECT  25.56 21.691 30.978 21.775 ;
     RECT  10.224 21.541 10.242 21.811 ;
     RECT  11.268 21.775 11.286 21.811 ;
     RECT  12.06 21.775 12.222 21.811 ;
     RECT  13.215 2.413 13.497 21.811 ;
     RECT  11.268 21.811 13.497 21.929 ;
     RECT  22.824 21.541 22.914 21.937 ;
     RECT  11.268 21.929 11.43 22.001 ;
     RECT  25.344 21.775 30.978 22.009 ;
     RECT  31.752 21.497 32.094 22.009 ;
     RECT  42.12 21.469 42.21 22.009 ;
     RECT  22.716 21.937 22.914 22.037 ;
     RECT  10.224 21.811 10.35 22.045 ;
     RECT  11.268 22.001 11.394 22.045 ;
     RECT  18.615 21.541 21.51 22.045 ;
     RECT  43.02 21.773 43.11 22.157 ;
     RECT  41.616 22.009 42.21 22.171 ;
     RECT  25.344 22.009 32.094 22.199 ;
     RECT  37.548 21.659 40.842 22.199 ;
     RECT  18.615 22.045 21.618 22.207 ;
     RECT  10.224 22.045 11.394 22.219 ;
     RECT  25.344 22.199 27.342 22.235 ;
     RECT  28.224 22.199 32.094 22.235 ;
     RECT  12.204 21.929 13.497 22.307 ;
     RECT  28.296 22.235 32.094 22.315 ;
     RECT  12.672 22.307 13.497 22.351 ;
     RECT  9.936 22.219 11.394 22.469 ;
     RECT  25.776 22.235 27.342 22.469 ;
     RECT  37.584 22.199 40.806 22.469 ;
     RECT  10.764 22.469 10.89 22.505 ;
     RECT  25.776 22.469 27.306 22.505 ;
     RECT  24.015 2.413 24.297 22.513 ;
     RECT  10.872 22.505 10.89 22.541 ;
     RECT  12.672 22.351 13.554 22.541 ;
     RECT  12.78 22.541 13.554 22.621 ;
     RECT  18.615 22.207 21.69 22.621 ;
     RECT  33.12 21.659 36.738 22.621 ;
     RECT  41.616 22.171 42.282 22.733 ;
     RECT  37.764 22.469 40.806 22.739 ;
     RECT  12.78 22.621 14.202 22.775 ;
     RECT  28.296 22.315 32.238 22.783 ;
     RECT  33.12 22.621 36.846 22.783 ;
     RECT  22.896 22.037 22.914 22.819 ;
     RECT  42.156 22.733 42.282 22.829 ;
     RECT  18.615 22.621 21.906 22.891 ;
     RECT  22.896 22.819 23.058 22.891 ;
     RECT  24.015 22.513 24.39 22.891 ;
     RECT  25.92 22.505 27.306 23.009 ;
     RECT  38.232 22.739 40.806 23.017 ;
     RECT  13.215 22.775 14.202 23.045 ;
     RECT  38.232 23.017 40.842 23.117 ;
     RECT  18.615 22.891 23.058 23.126 ;
     RECT  28.296 22.783 36.846 23.251 ;
     RECT  25.92 23.009 27.162 23.279 ;
     RECT  25.92 23.279 27.09 23.315 ;
     RECT  27.936 23.251 36.846 23.315 ;
     RECT  30.816 23.315 36.846 23.351 ;
     RECT  30.852 23.351 36.846 23.431 ;
     RECT  24.015 22.891 24.858 23.585 ;
     RECT  27.936 23.315 29.826 23.621 ;
     RECT  42.156 22.829 42.246 23.629 ;
     RECT  27.972 23.621 29.826 23.657 ;
     RECT  30.852 23.431 37.098 23.665 ;
     RECT  41.58 23.629 42.246 23.693 ;
     RECT  16.092 23.431 16.11 23.701 ;
     RECT  25.92 23.315 27.018 23.701 ;
     RECT  30.852 23.665 37.134 23.729 ;
     RECT  38.232 23.117 40.698 23.791 ;
     RECT  28.692 23.657 29.826 23.855 ;
     RECT  25.632 23.701 27.018 23.899 ;
     RECT  15.624 23.701 16.686 23.935 ;
     RECT  18.615 23.126 23.022 23.971 ;
     RECT  24.015 23.585 24.297 23.971 ;
     RECT  32.508 23.729 37.134 23.971 ;
     RECT  38.16 23.791 40.698 23.971 ;
     RECT  29.376 23.855 29.826 23.981 ;
     RECT  41.58 23.693 42.174 24.043 ;
     RECT  18.615 23.971 24.297 24.089 ;
     RECT  15.624 23.935 17.37 24.169 ;
     RECT  41.544 24.043 42.174 24.197 ;
     RECT  29.415 23.981 29.826 24.241 ;
     RECT  30.852 23.729 31.482 24.241 ;
     RECT  43.092 22.157 43.11 24.269 ;
     RECT  32.508 23.971 40.698 24.359 ;
     RECT  41.58 24.197 42.174 24.439 ;
     RECT  23.688 24.089 24.297 24.467 ;
     RECT  15.552 24.169 17.37 24.475 ;
     RECT  15.552 24.475 17.802 24.511 ;
     RECT  18.615 24.089 22.878 24.511 ;
     RECT  25.164 23.899 27.018 24.511 ;
     RECT  30.708 24.241 31.482 24.523 ;
     RECT  32.508 24.359 33.642 24.523 ;
     RECT  41.58 24.439 42.21 24.557 ;
     RECT  29.415 24.241 29.97 24.745 ;
     RECT  29.124 24.745 29.97 24.763 ;
     RECT  30.708 24.523 33.642 24.763 ;
     RECT  29.124 24.763 33.642 24.797 ;
     RECT  25.164 24.511 27.234 24.899 ;
     RECT  29.415 24.797 33.642 24.899 ;
     RECT  30.78 24.899 33.642 24.935 ;
     RECT  26.532 24.899 27.234 24.943 ;
     RECT  32.652 24.935 33.642 25.079 ;
     RECT  34.416 24.359 40.698 25.099 ;
     RECT  41.58 24.557 42.174 25.099 ;
     RECT  33.084 25.079 33.642 25.141 ;
     RECT  34.416 25.099 42.174 25.141 ;
     RECT  15.552 24.511 22.878 25.177 ;
     RECT  24.015 24.467 24.297 25.177 ;
     RECT  25.164 24.899 25.47 25.177 ;
     RECT  28.512 25.051 28.602 25.241 ;
     RECT  15.552 25.177 23.058 25.291 ;
     RECT  33.084 25.141 42.174 25.313 ;
     RECT  24.015 25.177 25.47 25.547 ;
     RECT  15.552 25.291 23.094 25.583 ;
     RECT  29.415 24.899 29.862 25.681 ;
     RECT  30.78 24.935 31.878 25.717 ;
     RECT  30.78 25.717 32.058 25.757 ;
     RECT  29.415 25.681 30.006 25.789 ;
     RECT  30.78 25.757 31.698 25.789 ;
     RECT  26.532 24.943 27.378 25.825 ;
     RECT  33.084 25.313 36.882 25.825 ;
     RECT  32.616 25.825 36.882 25.889 ;
     RECT  32.616 25.889 35.55 25.979 ;
     RECT  26.208 25.825 27.414 26.023 ;
     RECT  42.984 25.867 43.002 26.059 ;
     RECT  28.584 25.241 28.602 26.107 ;
     RECT  28.584 26.107 28.638 26.221 ;
     RECT  29.415 25.789 31.698 26.221 ;
     RECT  36.468 25.889 36.882 26.221 ;
     RECT  37.692 25.313 42.174 26.221 ;
     RECT  14.652 23.161 14.67 26.299 ;
     RECT  15.552 25.583 22.95 26.299 ;
     RECT  26.208 26.023 27.738 26.365 ;
     RECT  28.548 26.221 31.698 26.365 ;
     RECT  24.015 25.547 25.218 26.393 ;
     RECT  14.652 26.299 22.95 26.401 ;
     RECT  14.652 26.401 23.022 26.563 ;
     RECT  24.015 26.393 24.822 26.563 ;
     RECT  14.652 26.563 24.822 26.591 ;
     RECT  33.084 25.979 35.55 26.635 ;
     RECT  36.468 26.221 42.174 26.635 ;
     RECT  42.984 26.059 43.11 26.636 ;
     RECT  26.208 26.365 31.698 26.671 ;
     RECT  25.668 26.671 31.698 26.731 ;
     RECT  33.084 26.635 42.174 26.813 ;
     RECT  25.668 26.731 31.842 26.825 ;
     RECT  28.548 26.825 31.842 26.869 ;
     RECT  25.668 26.825 25.686 26.897 ;
     RECT  32.724 26.869 32.814 26.941 ;
     RECT  28.548 26.869 31.878 27.031 ;
     RECT  32.616 26.941 32.814 27.031 ;
     RECT  26.568 26.825 27.666 27.059 ;
     RECT  33.66 26.813 42.174 27.131 ;
     RECT  33.768 27.131 42.174 27.203 ;
     RECT  33.804 27.203 42.174 27.239 ;
     RECT  26.568 27.059 27.594 27.341 ;
     RECT  26.64 27.341 27.594 27.365 ;
     RECT  28.548 27.031 32.814 27.365 ;
     RECT  32.256 27.365 32.814 27.389 ;
     RECT  43.02 26.636 43.11 27.437 ;
     RECT  36.756 27.239 42.174 27.499 ;
     RECT  36.756 27.499 42.21 27.691 ;
     RECT  43.02 27.437 43.038 27.707 ;
     RECT  14.652 26.591 24.297 27.841 ;
     RECT  26.748 27.365 27.594 27.841 ;
     RECT  26.748 27.841 27.81 27.913 ;
     RECT  28.548 27.365 31.482 27.913 ;
     RECT  33.804 27.239 35.982 27.949 ;
     RECT  32.256 27.389 32.778 28.147 ;
     RECT  33.624 27.949 35.982 28.183 ;
     RECT  26.748 27.913 31.482 28.291 ;
     RECT  33.588 28.183 35.982 28.291 ;
     RECT  32.256 28.147 32.814 28.363 ;
     RECT  33.588 28.291 36.018 28.363 ;
     RECT  36.756 27.691 42.246 28.363 ;
     RECT  26.244 28.291 31.482 28.381 ;
     RECT  32.256 28.363 36.018 28.381 ;
     RECT  26.244 28.381 36.018 28.481 ;
     RECT  14.652 27.841 24.75 28.561 ;
     RECT  26.244 28.481 35.262 28.715 ;
     RECT  36 28.481 36.018 28.715 ;
     RECT  14.652 28.561 24.966 28.831 ;
     RECT  26.244 28.715 30.942 28.949 ;
     RECT  26.244 28.949 27.486 28.985 ;
     RECT  31.86 28.715 35.262 28.985 ;
     RECT  26.712 28.985 26.802 29.021 ;
     RECT  33.372 28.985 35.262 29.057 ;
     RECT  36.756 28.363 42.282 29.101 ;
     RECT  36.36 29.101 42.282 29.255 ;
     RECT  28.26 28.949 30.942 29.291 ;
     RECT  43.092 29.131 43.11 29.323 ;
     RECT  43.092 29.323 43.182 29.357 ;
     RECT  30.924 29.291 30.942 29.363 ;
     RECT  28.26 29.291 30.186 29.489 ;
     RECT  36.36 29.255 36.45 29.489 ;
     RECT  14.652 28.831 25.506 29.497 ;
     RECT  33.372 29.057 35.097 29.525 ;
     RECT  36.432 29.489 36.45 29.549 ;
     RECT  37.224 29.255 42.282 29.561 ;
     RECT  28.26 29.489 30.006 29.645 ;
     RECT  33.552 29.525 35.097 29.645 ;
     RECT  14.652 29.497 25.974 29.669 ;
     RECT  26.712 29.021 26.766 29.759 ;
     RECT  28.476 29.645 30.006 29.759 ;
     RECT  29.016 29.759 29.79 29.795 ;
     RECT  26.712 29.759 26.73 29.831 ;
     RECT  37.224 29.561 42.21 29.831 ;
     RECT  37.224 29.831 41.634 29.867 ;
     RECT  29.415 29.795 29.79 30.029 ;
     RECT  31.86 28.985 32.634 30.479 ;
     RECT  31.86 30.479 32.346 30.911 ;
     RECT  31.86 30.911 32.094 31.019 ;
     RECT  37.764 29.867 41.634 31.019 ;
     RECT  14.652 29.669 25.902 31.145 ;
     RECT  37.764 31.019 41.49 31.379 ;
     RECT  31.86 31.019 31.878 31.487 ;
     RECT  33.588 29.645 35.097 31.523 ;
     RECT  33.588 31.523 33.606 31.559 ;
     RECT  38.448 31.379 41.49 31.919 ;
     RECT  14.76 31.145 25.902 32.035 ;
     RECT  34.416 31.523 35.097 32.333 ;
     RECT  34.524 32.333 35.097 32.369 ;
     RECT  38.448 31.919 41.094 32.459 ;
     RECT  43.164 29.357 43.182 32.729 ;
     RECT  39.204 32.459 41.094 32.837 ;
     RECT  39.204 32.837 41.058 32.909 ;
     RECT  14.364 32.035 25.902 32.999 ;
     RECT  38.448 32.459 38.466 32.999 ;
     RECT  39.492 32.909 41.058 32.999 ;
     RECT  39.6 32.999 40.497 33.035 ;
     RECT  14.364 32.999 22.554 33.925 ;
     RECT  23.292 32.999 25.902 33.925 ;
     RECT  14.364 33.925 25.902 34.889 ;
     RECT  13.215 23.045 13.497 36.661 ;
     RECT  14.364 34.889 25.686 36.661 ;
     RECT  13.215 36.661 25.686 38.939 ;
     RECT  13.215 38.939 24.57 39.181 ;
     RECT  13.176 39.181 24.57 39.721 ;
     RECT  25.38 38.939 25.686 39.721 ;
     RECT  13.176 39.721 25.686 40.019 ;
     RECT  13.176 40.019 25.002 40.055 ;
     RECT  13.215 40.055 25.002 40.559 ;
     RECT  2.415 21.425 2.697 40.787 ;
     RECT  7.815 2.413 8.097 40.787 ;
     RECT  13.215 40.559 24.894 40.787 ;
     RECT  29.415 30.029 29.697 40.787 ;
     RECT  34.815 32.369 35.097 40.787 ;
     RECT  40.215 33.035 40.497 40.787 ;
     RECT  24.876 40.787 24.894 40.829 ;
     RECT  13.215 40.787 24.105 40.937 ;
     RECT  13.215 40.937 23.238 41.009 ;
     RECT  23.976 40.937 24.105 41.009 ;
     RECT  13.215 41.009 15.606 41.021 ;
     RECT  16.38 41.009 23.238 41.021 ;
     RECT  2.415 40.787 2.505 41.057 ;
     RECT  7.815 40.787 7.905 41.057 ;
     RECT  13.215 41.021 14.634 41.057 ;
     RECT  24.015 41.009 24.105 41.057 ;
     RECT  29.415 40.787 29.505 41.057 ;
     RECT  34.815 40.787 34.905 41.057 ;
     RECT  40.215 40.787 40.305 41.057 ;
     RECT  17.352 41.021 19.386 41.069 ;
     RECT  17.748 41.069 19.386 41.645 ;
     RECT  19.368 41.645 19.386 42.173 ;
     RECT  13.572 41.057 14.634 42.221 ;
     RECT  17.748 41.645 18.558 42.221 ;
     RECT  13.608 42.221 14.634 42.269 ;
     RECT  17.748 42.221 18.522 42.269 ;
     RECT  18.216 42.269 18.522 42.317 ;
     RECT  13.608 42.269 14.49 42.365 ;
     RECT  18.504 42.317 18.522 42.365 ;
     RECT  21.6 41.021 22.23 42.797 ;
     RECT  13.608 42.365 14.238 42.989 ;
     RECT  15.372 41.021 15.498 43.037 ;
     RECT  13.608 42.989 14.202 43.085 ;
     RECT  15.372 43.037 15.39 43.085 ;
     RECT  16.488 41.021 16.506 43.085 ;
     RECT  22.212 42.797 22.23 43.085 ;
    LAYER M4 ;
     RECT  0.06 20.976 0.227 21.096 ;
     RECT  0.227 21.072 2.408 21.096 ;
     RECT  0.181 30.336 2.408 30.36 ;
     RECT  2.408 2.148 2.512 41.052 ;
     RECT  2.512 2.418 2.704 40.782 ;
     RECT  2.704 30.336 7.808 30.36 ;
     RECT  7.808 2.148 7.912 41.052 ;
     RECT  7.912 2.418 8.104 40.782 ;
     RECT  9.925 22.224 12.661 22.248 ;
     RECT  12.661 22.224 13.208 22.536 ;
     RECT  8.104 30.336 13.208 30.36 ;
     RECT  13.208 2.148 13.312 41.052 ;
     RECT  13.312 2.418 13.504 41.052 ;
     RECT  13.561 42.192 13.597 42.216 ;
     RECT  13.504 40.464 13.633 41.052 ;
     RECT  13.597 42.192 13.633 43.08 ;
     RECT  13.633 40.464 14.291 43.08 ;
     RECT  14.291 40.464 14.675 42.984 ;
     RECT  13.504 37.296 15.157 38.232 ;
     RECT  14.675 42.192 15.251 42.984 ;
     RECT  15.157 37.296 15.257 39.432 ;
     RECT  15.251 42.24 15.347 42.984 ;
     RECT  15.347 42.288 15.361 42.984 ;
     RECT  15.361 42.288 15.539 43.08 ;
     RECT  15.577 35.328 15.589 35.352 ;
     RECT  15.577 31.872 15.661 31.896 ;
     RECT  15.589 34.8 15.685 35.352 ;
     RECT  15.397 33.6 15.692 33.624 ;
     RECT  15.685 34.8 15.725 35.832 ;
     RECT  13.504 22.512 15.779 22.536 ;
     RECT  15.692 33.504 15.779 33.624 ;
     RECT  15.725 35.28 15.793 35.832 ;
     RECT  15.257 37.296 15.793 38.856 ;
     RECT  15.539 43.008 16.019 43.08 ;
     RECT  15.793 35.28 16.765 38.856 ;
     RECT  16.765 35.28 16.873 39.144 ;
     RECT  14.675 40.464 16.873 41.016 ;
     RECT  16.019 43.056 16.979 43.08 ;
     RECT  16.873 35.28 17.123 41.016 ;
     RECT  17.123 35.328 17.165 41.016 ;
     RECT  17.165 37.056 17.28 41.016 ;
     RECT  17.28 37.056 17.406 41.064 ;
     RECT  15.779 33.6 17.507 33.624 ;
     RECT  17.165 35.328 18.181 35.976 ;
     RECT  17.406 37.056 18.181 41.016 ;
     RECT  17.737 42.24 18.205 42.264 ;
     RECT  18.205 42.24 18.241 42.312 ;
     RECT  18.241 42.192 18.493 42.312 ;
     RECT  18.181 35.328 18.565 41.016 ;
     RECT  14.965 26.304 18.608 26.328 ;
     RECT  13.504 30.336 18.608 30.36 ;
     RECT  18.565 35.328 18.608 41.16 ;
     RECT  18.608 2.148 18.661 41.16 ;
     RECT  18.661 2.148 18.712 41.208 ;
     RECT  18.712 2.418 18.737 41.208 ;
     RECT  18.493 42.192 18.737 42.36 ;
     RECT  18.737 2.418 18.904 42.36 ;
     RECT  18.904 38.544 19.073 42.36 ;
     RECT  18.904 35.328 19.132 36.36 ;
     RECT  19.073 39.648 19.189 42.36 ;
     RECT  19.073 38.544 19.235 38.568 ;
     RECT  19.189 39.648 19.379 43.032 ;
     RECT  18.904 37.44 19.397 37.464 ;
     RECT  19.379 39.648 19.475 42.168 ;
     RECT  19.475 39.648 19.571 41.64 ;
     RECT  19.571 39.648 20.081 41.016 ;
     RECT  19.132 35.424 20.113 36.36 ;
     RECT  20.113 34.752 20.149 36.36 ;
     RECT  20.149 34.752 20.197 36.504 ;
     RECT  20.081 40.416 20.339 41.016 ;
     RECT  20.197 35.664 20.437 36.504 ;
     RECT  20.437 35.664 20.629 37.224 ;
     RECT  20.629 35.664 20.693 37.848 ;
     RECT  20.693 37.008 20.716 37.848 ;
     RECT  20.693 35.664 20.801 35.88 ;
     RECT  20.716 37.008 20.819 37.224 ;
     RECT  20.339 40.464 20.915 41.016 ;
     RECT  20.819 37.2 21.125 37.224 ;
     RECT  20.185 39.312 21.125 39.336 ;
     RECT  20.915 40.848 21.203 41.016 ;
     RECT  21.589 42.768 21.683 42.792 ;
     RECT  22.201 43.056 22.285 43.08 ;
     RECT  21.203 40.896 22.417 41.016 ;
     RECT  22.417 40.464 22.669 41.016 ;
     RECT  18.904 26.256 22.885 26.328 ;
     RECT  22.669 39.84 22.961 41.016 ;
     RECT  22.885 23.232 23.033 23.256 ;
     RECT  18.904 30.336 23.605 30.36 ;
     RECT  23.353 38.688 23.929 38.712 ;
     RECT  22.885 25.296 24.008 26.328 ;
     RECT  23.605 30.336 24.008 30.6 ;
     RECT  20.801 35.856 24.008 35.88 ;
     RECT  23.929 38.688 24.008 38.808 ;
     RECT  22.961 40.464 24.008 41.016 ;
     RECT  24.008 2.148 24.112 41.052 ;
     RECT  24.112 2.418 24.304 40.782 ;
     RECT  24.304 30.144 24.419 30.696 ;
     RECT  24.304 38.784 24.437 38.808 ;
     RECT  26.557 27.312 26.737 27.336 ;
     RECT  26.737 27.312 26.849 27.384 ;
     RECT  26.557 23.136 27.173 23.16 ;
     RECT  26.849 27.36 27.425 27.384 ;
     RECT  24.304 26.256 27.533 26.328 ;
     RECT  24.419 30.24 28.249 30.264 ;
     RECT  28.285 22.848 28.393 22.872 ;
     RECT  28.393 22.848 28.493 23.256 ;
     RECT  28.493 22.752 28.501 23.256 ;
     RECT  27.533 26.304 28.609 26.328 ;
     RECT  28.249 29.616 28.825 30.264 ;
     RECT  28.501 22.752 29.365 23.688 ;
     RECT  29.113 24.768 29.365 24.792 ;
     RECT  28.969 21.696 29.408 21.72 ;
     RECT  29.365 22.752 29.408 24.792 ;
     RECT  28.609 26.112 29.408 26.328 ;
     RECT  29.221 27.888 29.408 27.912 ;
     RECT  28.825 29.088 29.408 30.264 ;
     RECT  29.408 2.148 29.512 41.052 ;
     RECT  29.512 2.418 29.704 40.782 ;
     RECT  29.704 20.976 29.801 29.448 ;
     RECT  29.801 24.768 30.083 29.448 ;
     RECT  30.083 24.768 30.233 29.016 ;
     RECT  29.801 20.976 30.881 23.4 ;
     RECT  30.881 20.976 30.989 23.16 ;
     RECT  30.233 24.768 31.093 28.392 ;
     RECT  31.093 24.72 31.309 28.392 ;
     RECT  31.309 24.624 31.457 28.392 ;
     RECT  30.989 20.976 31.709 21 ;
     RECT  31.457 24.624 31.777 25.752 ;
     RECT  31.457 26.736 31.853 28.392 ;
     RECT  30.989 22.032 31.861 23.16 ;
     RECT  31.777 24.528 31.907 25.752 ;
     RECT  31.861 22.032 32.033 23.352 ;
     RECT  31.853 26.928 32.396 28.392 ;
     RECT  32.396 26.928 32.483 29.352 ;
     RECT  32.033 22.032 33.061 23.16 ;
     RECT  31.907 24.672 33.061 25.752 ;
     RECT  32.483 26.928 33.107 28.392 ;
     RECT  33.061 22.032 33.149 25.752 ;
     RECT  33.107 26.928 33.181 27.384 ;
     RECT  33.149 22.032 33.185 24.84 ;
     RECT  33.107 28.368 33.257 28.392 ;
     RECT  33.181 26.784 33.361 27.384 ;
     RECT  33.185 24.48 33.617 24.84 ;
     RECT  32.389 20.832 34.153 20.856 ;
     RECT  33.185 22.032 34.153 23.448 ;
     RECT  33.541 29.616 34.261 29.64 ;
     RECT  33.361 26.016 34.693 27.384 ;
     RECT  34.153 20.832 34.765 23.448 ;
     RECT  34.693 26.016 34.765 27.48 ;
     RECT  34.765 20.304 34.808 23.448 ;
     RECT  33.617 24.48 34.808 24.792 ;
     RECT  34.765 26.016 34.808 28.44 ;
     RECT  34.261 29.52 34.808 29.64 ;
     RECT  34.808 2.148 34.912 41.052 ;
     RECT  34.912 2.418 35.104 40.782 ;
     RECT  35.104 26.016 35.381 28.44 ;
     RECT  35.381 26.016 35.561 26.04 ;
     RECT  35.381 27.36 35.705 28.44 ;
     RECT  35.104 19.92 35.843 23.736 ;
     RECT  35.705 27.888 35.993 28.44 ;
     RECT  35.843 20.304 36.029 23.736 ;
     RECT  36.029 20.304 36.101 21.624 ;
     RECT  36.101 20.304 36.137 20.328 ;
     RECT  36.029 22.752 36.461 23.736 ;
     RECT  35.104 29.52 36.461 29.544 ;
     RECT  35.104 24.912 36.677 24.984 ;
     RECT  35.993 27.888 37.033 27.912 ;
     RECT  36.461 23.712 37.037 23.736 ;
     RECT  37.033 27.888 37.091 28.536 ;
     RECT  37.091 28.512 37.117 28.536 ;
     RECT  36.677 24.96 37.649 24.984 ;
     RECT  38.437 27.216 38.545 27.24 ;
     RECT  38.545 27.216 38.869 27.336 ;
     RECT  38.149 23.856 38.977 23.88 ;
     RECT  38.977 23.712 39.049 23.88 ;
     RECT  38.545 21.12 39.265 21.144 ;
     RECT  38.869 26.88 39.265 27.336 ;
     RECT  39.265 26.88 39.445 27.432 ;
     RECT  39.265 21.12 39.661 21.96 ;
     RECT  39.049 23.712 39.661 24.6 ;
     RECT  39.661 21.12 39.733 24.6 ;
     RECT  39.445 26.592 39.805 27.432 ;
     RECT  39.805 26.592 39.877 27.624 ;
     RECT  39.733 21.12 39.985 24.648 ;
     RECT  39.877 26.592 39.985 27.864 ;
     RECT  39.985 20.304 40.129 24.648 ;
     RECT  40.129 19.776 40.208 24.648 ;
     RECT  39.985 26.592 40.208 27.912 ;
     RECT  40.208 2.148 40.312 41.052 ;
     RECT  40.312 2.418 40.504 40.782 ;
     RECT  40.504 24.624 41.497 25.224 ;
     RECT  40.504 26.448 41.497 29.256 ;
     RECT  40.504 19.92 41.533 23.4 ;
     RECT  41.497 24.624 41.533 29.256 ;
     RECT  41.533 19.92 43.081 29.256 ;
     RECT  43.081 19.92 43.164 29.352 ;
     RECT  43.164 29.328 43.193 29.352 ;
    LAYER M5 ;
     RECT  2.4 2.137 2.52 2.151 ;
     RECT  7.8 2.137 7.92 2.151 ;
     RECT  13.2 2.137 13.32 2.151 ;
     RECT  18.6 2.137 18.72 2.151 ;
     RECT  24 2.137 24.12 2.151 ;
     RECT  29.4 2.137 29.52 2.151 ;
     RECT  34.8 2.137 34.92 2.151 ;
     RECT  40.2 2.137 40.32 2.151 ;
     RECT  34.8 2.151 35.112 19.909 ;
     RECT  34.8 19.909 35.832 21.589 ;
     RECT  29.4 2.151 29.712 22.597 ;
     RECT  29.4 22.597 30.648 22.741 ;
     RECT  33.456 22.021 33.48 23.317 ;
     RECT  34.8 21.589 35.88 23.317 ;
     RECT  33.072 23.317 33.48 23.363 ;
     RECT  28.512 22.741 30.648 23.411 ;
     RECT  34.704 23.317 35.88 23.411 ;
     RECT  34.704 23.411 35.112 23.459 ;
     RECT  28.512 23.411 29.712 23.699 ;
     RECT  31.872 23.317 31.896 24.563 ;
     RECT  29.4 23.699 29.712 24.757 ;
     RECT  29.232 24.757 29.712 25.717 ;
     RECT  29.232 25.717 30.216 26.243 ;
     RECT  34.8 23.459 35.112 26.725 ;
     RECT  34.704 26.725 35.112 27.491 ;
     RECT  33.072 23.363 33.096 27.923 ;
     RECT  29.232 26.243 29.712 28.357 ;
     RECT  37.056 27.877 37.08 28.547 ;
     RECT  32.448 28.357 32.472 29.363 ;
     RECT  29.232 28.357 30.072 29.459 ;
     RECT  24 2.151 24.312 30.133 ;
     RECT  29.232 29.459 29.712 30.275 ;
     RECT  0.192 20.965 0.216 30.371 ;
     RECT  24 30.133 24.408 30.565 ;
     RECT  23.616 30.565 24.408 30.707 ;
     RECT  15.744 22.501 15.768 31.861 ;
     RECT  17.472 33.589 17.496 35.269 ;
     RECT  15.6 31.861 15.768 35.315 ;
     RECT  18.6 2.151 18.912 35.317 ;
     RECT  20.16 34.741 20.184 35.845 ;
     RECT  23.616 30.707 24.312 35.891 ;
     RECT  17.088 35.269 17.496 35.987 ;
     RECT  20.16 35.845 20.808 36.515 ;
     RECT  17.472 35.987 17.496 36.565 ;
     RECT  18.6 35.317 19.08 36.565 ;
     RECT  20.64 36.515 20.808 37.043 ;
     RECT  17.472 36.565 19.08 37.045 ;
     RECT  20.64 37.043 20.664 37.859 ;
     RECT  15.6 35.315 15.624 38.149 ;
     RECT  17.376 37.045 19.08 38.533 ;
     RECT  17.376 38.533 19.224 38.581 ;
     RECT  15.168 38.149 15.624 38.773 ;
     RECT  17.328 38.581 19.224 38.773 ;
     RECT  15.168 38.773 19.224 38.819 ;
     RECT  15.168 38.819 15.192 39.443 ;
     RECT  13.2 2.151 13.512 40.453 ;
     RECT  16.56 38.819 19.224 40.453 ;
     RECT  20.304 40.405 20.328 40.453 ;
     RECT  13.2 40.453 20.904 40.837 ;
     RECT  13.2 40.837 21.192 40.885 ;
     RECT  22.512 40.453 22.632 40.885 ;
     RECT  23.712 35.891 24.312 40.885 ;
     RECT  2.4 2.151 2.712 41.049 ;
     RECT  7.8 2.151 8.112 41.049 ;
     RECT  13.2 40.885 24.312 41.049 ;
     RECT  29.4 30.275 29.712 41.049 ;
     RECT  34.8 27.491 35.112 41.049 ;
     RECT  40.2 2.151 40.512 41.049 ;
     RECT  2.4 41.049 2.52 41.063 ;
     RECT  7.8 41.049 7.92 41.063 ;
     RECT  13.2 41.049 24.12 41.063 ;
     RECT  29.4 41.049 29.52 41.063 ;
     RECT  34.8 41.049 34.92 41.063 ;
     RECT  40.2 41.049 40.32 41.063 ;
     RECT  14.064 41.063 23.208 42.181 ;
     RECT  13.968 42.181 23.208 43.045 ;
     RECT  13.872 43.045 23.208 43.152 ;
     RECT  33.48 22.021 34.8 23.317 ;
     RECT  30.648 23.317 31.872 23.411 ;
     RECT  31.896 23.317 33.072 24.563 ;
     RECT  33.48 23.317 34.704 23.363 ;
     RECT  29.232 23.699 29.4 24.757 ;
     RECT  17.496 33.589 18.6 36.565 ;
     RECT  18.912 34.741 20.16 35.317 ;
     RECT  15.768 35.269 17.088 35.315 ;
     RECT  15.624 35.315 17.088 35.987 ;
     RECT  19.08 35.317 20.16 36.515 ;
     RECT  17.376 35.987 17.472 37.045 ;
     RECT  15.192 38.819 16.56 39.443 ;
     RECT  15.168 39.443 16.56 40.453 ;
     RECT  19.224 40.405 20.304 40.453 ;
     RECT  22.632 40.453 23.712 40.885 ;
     RECT  21.192 40.837 22.512 40.885 ;
     RECT  13.968 41.063 14.064 42.181 ;
  END
END ot_qkh_head_stout_native
END LIBRARY
